VERSION 5.7 ;
  NOWIREEXTENSIONATPIN ON ;
  DIVIDERCHAR "/" ;
  BUSBITCHARS "[]" ;
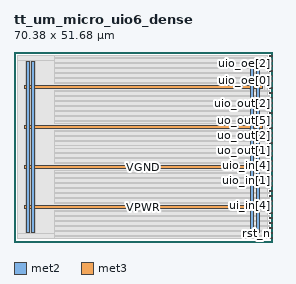
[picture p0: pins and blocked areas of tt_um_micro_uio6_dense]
MACRO tt_um_micro_uio6_dense
  CLASS BLOCK ;
  FOREIGN tt_um_micro_uio6_dense ;
  ORIGIN 0.000 0.000 ;
  SIZE 70.380 BY 51.680 ;
  PIN VGND
    DIRECTION INOUT ;
    USE GROUND ;
    PORT
      LAYER met2 ;
        RECT 4.660 2.480 5.460 49.200 ;
    END
    PORT
      LAYER met2 ;
        RECT 65.840 2.480 66.640 49.200 ;
    END
    PORT
      LAYER met3 ;
        RECT 2.760 19.900 67.620 20.900 ;
    END
    PORT
      LAYER met3 ;
        RECT 2.760 41.660 67.620 42.660 ;
    END
  END VGND
  PIN VPWR
    DIRECTION INOUT ;
    USE POWER ;
    PORT
      LAYER met2 ;
        RECT 3.280 2.480 4.080 49.200 ;
    END
    PORT
      LAYER met2 ;
        RECT 64.460 2.480 65.260 49.200 ;
    END
    PORT
      LAYER met3 ;
        RECT 2.760 9.020 67.620 10.020 ;
    END
    PORT
      LAYER met3 ;
        RECT 2.760 30.780 67.620 31.780 ;
    END
  END VPWR
  PIN clk
    DIRECTION INPUT ;
    USE SIGNAL ;
    ANTENNAGATEAREA 0.852000 ;
    PORT
      LAYER met3 ;
        RECT 69.380 0.870 70.380 1.170 ;
    END
  END clk
  PIN rst_n
    DIRECTION INPUT ;
    USE SIGNAL ;
    ANTENNAGATEAREA 0.213000 ;
    PORT
      LAYER met3 ;
        RECT 69.380 2.230 70.380 2.530 ;
    END
  END rst_n
  PIN ui_in[0]
    DIRECTION INPUT ;
    USE SIGNAL ;
    ANTENNAGATEAREA 0.213000 ;
    PORT
      LAYER met3 ;
        RECT 69.380 3.590 70.380 3.890 ;
    END
  END ui_in[0]
  PIN ui_in[1]
    DIRECTION INPUT ;
    USE SIGNAL ;
    ANTENNAGATEAREA 0.196500 ;
    PORT
      LAYER met3 ;
        RECT 69.380 4.950 70.380 5.250 ;
    END
  END ui_in[1]
  PIN ui_in[2]
    DIRECTION INPUT ;
    USE SIGNAL ;
    ANTENNAGATEAREA 0.196500 ;
    PORT
      LAYER met3 ;
        RECT 69.380 6.310 70.380 6.610 ;
    END
  END ui_in[2]
  PIN ui_in[3]
    DIRECTION INPUT ;
    USE SIGNAL ;
    ANTENNAGATEAREA 0.196500 ;
    PORT
      LAYER met3 ;
        RECT 69.380 7.670 70.380 7.970 ;
    END
  END ui_in[3]
  PIN ui_in[4]
    DIRECTION INPUT ;
    USE SIGNAL ;
    ANTENNAGATEAREA 0.213000 ;
    PORT
      LAYER met3 ;
        RECT 69.380 9.710 70.380 10.010 ;
    END
  END ui_in[4]
  PIN ui_in[5]
    DIRECTION INPUT ;
    USE SIGNAL ;
    ANTENNAGATEAREA 0.213000 ;
    PORT
      LAYER met3 ;
        RECT 69.380 11.070 70.380 11.370 ;
    END
  END ui_in[5]
  PIN ui_in[6]
    DIRECTION INPUT ;
    USE SIGNAL ;
    ANTENNAGATEAREA 0.213000 ;
    PORT
      LAYER met3 ;
        RECT 69.380 12.430 70.380 12.730 ;
    END
  END ui_in[6]
  PIN ui_in[7]
    DIRECTION INPUT ;
    USE SIGNAL ;
    ANTENNAGATEAREA 0.213000 ;
    PORT
      LAYER met3 ;
        RECT 69.380 13.790 70.380 14.090 ;
    END
  END ui_in[7]
  PIN uio_in[0]
    DIRECTION INPUT ;
    USE SIGNAL ;
    ANTENNAGATEAREA 0.213000 ;
    PORT
      LAYER met3 ;
        RECT 69.380 15.150 70.380 15.450 ;
    END
  END uio_in[0]
  PIN uio_in[1]
    DIRECTION INPUT ;
    USE SIGNAL ;
    ANTENNAGATEAREA 0.213000 ;
    PORT
      LAYER met3 ;
        RECT 69.380 16.510 70.380 16.810 ;
    END
  END uio_in[1]
  PIN uio_in[2]
    DIRECTION INPUT ;
    USE SIGNAL ;
    ANTENNAGATEAREA 0.213000 ;
    PORT
      LAYER met3 ;
        RECT 69.380 17.870 70.380 18.170 ;
    END
  END uio_in[2]
  PIN uio_in[3]
    DIRECTION INPUT ;
    USE SIGNAL ;
    ANTENNAGATEAREA 0.213000 ;
    PORT
      LAYER met3 ;
        RECT 69.380 19.230 70.380 19.530 ;
    END
  END uio_in[3]
  PIN uio_in[4]
    DIRECTION INPUT ;
    USE SIGNAL ;
    ANTENNAGATEAREA 0.213000 ;
    PORT
      LAYER met3 ;
        RECT 69.380 20.590 70.380 20.890 ;
    END
  END uio_in[4]
  PIN uio_in[5]
    DIRECTION INPUT ;
    USE SIGNAL ;
    ANTENNAGATEAREA 0.213000 ;
    PORT
      LAYER met3 ;
        RECT 69.380 21.950 70.380 22.250 ;
    END
  END uio_in[5]
  PIN uio_oe[0]
    DIRECTION OUTPUT ;
    USE SIGNAL ;
    ANTENNADIFFAREA 0.429000 ;
    PORT
      LAYER met3 ;
        RECT 69.380 43.710 70.380 44.010 ;
    END
  END uio_oe[0]
  PIN uio_oe[1]
    DIRECTION OUTPUT ;
    USE SIGNAL ;
    ANTENNADIFFAREA 0.429000 ;
    PORT
      LAYER met3 ;
        RECT 69.380 45.070 70.380 45.370 ;
    END
  END uio_oe[1]
  PIN uio_oe[2]
    DIRECTION OUTPUT ;
    USE SIGNAL ;
    ANTENNADIFFAREA 0.429000 ;
    PORT
      LAYER met3 ;
        RECT 69.380 46.430 70.380 46.730 ;
    END
  END uio_oe[2]
  PIN uio_oe[3]
    DIRECTION OUTPUT ;
    USE SIGNAL ;
    ANTENNADIFFAREA 0.429000 ;
    PORT
      LAYER met3 ;
        RECT 69.380 47.790 70.380 48.090 ;
    END
  END uio_oe[3]
  PIN uio_oe[4]
    DIRECTION OUTPUT ;
    USE SIGNAL ;
    ANTENNADIFFAREA 0.429000 ;
    PORT
      LAYER met3 ;
        RECT 69.380 49.150 70.380 49.450 ;
    END
  END uio_oe[4]
  PIN uio_oe[5]
    DIRECTION OUTPUT ;
    USE SIGNAL ;
    ANTENNADIFFAREA 0.429000 ;
    PORT
      LAYER met3 ;
        RECT 69.380 50.510 70.380 50.810 ;
    END
  END uio_oe[5]
  PIN uio_out[0]
    DIRECTION OUTPUT ;
    USE SIGNAL ;
    ANTENNADIFFAREA 0.429000 ;
    PORT
      LAYER met3 ;
        RECT 69.380 34.870 70.380 35.170 ;
    END
  END uio_out[0]
  PIN uio_out[1]
    DIRECTION OUTPUT ;
    USE SIGNAL ;
    ANTENNADIFFAREA 0.445500 ;
    PORT
      LAYER met3 ;
        RECT 69.380 36.230 70.380 36.530 ;
    END
  END uio_out[1]
  PIN uio_out[2]
    DIRECTION OUTPUT ;
    USE SIGNAL ;
    ANTENNADIFFAREA 0.445500 ;
    PORT
      LAYER met3 ;
        RECT 69.380 37.590 70.380 37.890 ;
    END
  END uio_out[2]
  PIN uio_out[3]
    DIRECTION OUTPUT ;
    USE SIGNAL ;
    ANTENNADIFFAREA 0.429000 ;
    PORT
      LAYER met3 ;
        RECT 69.380 38.950 70.380 39.250 ;
    END
  END uio_out[3]
  PIN uio_out[4]
    DIRECTION OUTPUT ;
    USE SIGNAL ;
    ANTENNADIFFAREA 0.445500 ;
    PORT
      LAYER met3 ;
        RECT 69.380 40.310 70.380 40.610 ;
    END
  END uio_out[4]
  PIN uio_out[5]
    DIRECTION OUTPUT ;
    USE SIGNAL ;
    ANTENNADIFFAREA 0.445500 ;
    PORT
      LAYER met3 ;
        RECT 69.380 41.670 70.380 41.970 ;
    END
  END uio_out[5]
  PIN uo_out[0]
    DIRECTION OUTPUT ;
    USE SIGNAL ;
    ANTENNADIFFAREA 0.429000 ;
    PORT
      LAYER met3 ;
        RECT 69.380 23.310 70.380 23.610 ;
    END
  END uo_out[0]
  PIN uo_out[1]
    DIRECTION OUTPUT ;
    USE SIGNAL ;
    ANTENNADIFFAREA 0.429000 ;
    PORT
      LAYER met3 ;
        RECT 69.380 24.670 70.380 24.970 ;
    END
  END uo_out[1]
  PIN uo_out[2]
    DIRECTION OUTPUT ;
    USE SIGNAL ;
    ANTENNADIFFAREA 0.429000 ;
    PORT
      LAYER met3 ;
        RECT 69.380 26.710 70.380 27.010 ;
    END
  END uo_out[2]
  PIN uo_out[3]
    DIRECTION OUTPUT ;
    USE SIGNAL ;
    ANTENNADIFFAREA 0.429000 ;
    PORT
      LAYER met3 ;
        RECT 69.380 28.070 70.380 28.370 ;
    END
  END uo_out[3]
  PIN uo_out[4]
    DIRECTION OUTPUT ;
    USE SIGNAL ;
    ANTENNADIFFAREA 0.462000 ;
    PORT
      LAYER met3 ;
        RECT 69.380 29.430 70.380 29.730 ;
    END
  END uo_out[4]
  PIN uo_out[5]
    DIRECTION OUTPUT ;
    USE SIGNAL ;
    ANTENNADIFFAREA 0.445500 ;
    PORT
      LAYER met3 ;
        RECT 69.380 30.790 70.380 31.090 ;
    END
  END uo_out[5]
  PIN uo_out[6]
    DIRECTION OUTPUT ;
    USE SIGNAL ;
    ANTENNADIFFAREA 0.445500 ;
    PORT
      LAYER met3 ;
        RECT 69.380 32.150 70.380 32.450 ;
    END
  END uo_out[6]
  PIN uo_out[7]
    DIRECTION OUTPUT ;
    USE SIGNAL ;
    ANTENNADIFFAREA 0.445500 ;
    PORT
      LAYER met3 ;
        RECT 69.380 33.510 70.380 33.810 ;
    END
  END uo_out[7]
  OBS
      LAYER nwell ;
        RECT 2.570 2.635 67.810 49.150 ;
      LAYER li1 ;
        RECT 2.760 2.635 67.620 49.045 ;
      LAYER met1 ;
        RECT 0.990 1.400 68.470 49.200 ;
      LAYER met2 ;
        RECT 1.020 49.480 68.450 50.845 ;
        RECT 1.020 2.200 3.000 49.480 ;
        RECT 4.360 2.200 4.380 49.480 ;
        RECT 5.740 2.200 64.180 49.480 ;
        RECT 65.540 2.200 65.560 49.480 ;
        RECT 66.920 2.200 68.450 49.480 ;
        RECT 1.020 0.835 68.450 2.200 ;
      LAYER met3 ;
        RECT 11.105 50.110 68.980 50.825 ;
        RECT 11.105 49.850 69.380 50.110 ;
        RECT 11.105 48.750 68.980 49.850 ;
        RECT 11.105 48.490 69.380 48.750 ;
        RECT 11.105 47.390 68.980 48.490 ;
        RECT 11.105 47.130 69.380 47.390 ;
        RECT 11.105 46.030 68.980 47.130 ;
        RECT 11.105 45.770 69.380 46.030 ;
        RECT 11.105 44.670 68.980 45.770 ;
        RECT 11.105 44.410 69.380 44.670 ;
        RECT 11.105 43.310 68.980 44.410 ;
        RECT 11.105 43.060 69.380 43.310 ;
        RECT 68.020 42.370 69.380 43.060 ;
        RECT 68.020 41.270 68.980 42.370 ;
        RECT 68.020 41.260 69.380 41.270 ;
        RECT 11.105 41.010 69.380 41.260 ;
        RECT 11.105 39.910 68.980 41.010 ;
        RECT 11.105 39.650 69.380 39.910 ;
        RECT 11.105 38.550 68.980 39.650 ;
        RECT 11.105 38.290 69.380 38.550 ;
        RECT 11.105 37.190 68.980 38.290 ;
        RECT 11.105 36.930 69.380 37.190 ;
        RECT 11.105 35.830 68.980 36.930 ;
        RECT 11.105 35.570 69.380 35.830 ;
        RECT 11.105 34.470 68.980 35.570 ;
        RECT 11.105 34.210 69.380 34.470 ;
        RECT 11.105 33.110 68.980 34.210 ;
        RECT 11.105 32.850 69.380 33.110 ;
        RECT 11.105 32.180 68.980 32.850 ;
        RECT 68.020 31.750 68.980 32.180 ;
        RECT 68.020 31.490 69.380 31.750 ;
        RECT 68.020 30.390 68.980 31.490 ;
        RECT 68.020 30.380 69.380 30.390 ;
        RECT 11.105 30.130 69.380 30.380 ;
        RECT 11.105 29.030 68.980 30.130 ;
        RECT 11.105 28.770 69.380 29.030 ;
        RECT 11.105 27.670 68.980 28.770 ;
        RECT 11.105 27.410 69.380 27.670 ;
        RECT 11.105 26.310 68.980 27.410 ;
        RECT 11.105 25.370 69.380 26.310 ;
        RECT 11.105 24.270 68.980 25.370 ;
        RECT 11.105 24.010 69.380 24.270 ;
        RECT 11.105 22.910 68.980 24.010 ;
        RECT 11.105 22.650 69.380 22.910 ;
        RECT 11.105 21.550 68.980 22.650 ;
        RECT 11.105 21.300 69.380 21.550 ;
        RECT 68.020 21.290 69.380 21.300 ;
        RECT 68.020 20.190 68.980 21.290 ;
        RECT 68.020 19.930 69.380 20.190 ;
        RECT 68.020 19.500 68.980 19.930 ;
        RECT 11.105 18.830 68.980 19.500 ;
        RECT 11.105 18.570 69.380 18.830 ;
        RECT 11.105 17.470 68.980 18.570 ;
        RECT 11.105 17.210 69.380 17.470 ;
        RECT 11.105 16.110 68.980 17.210 ;
        RECT 11.105 15.850 69.380 16.110 ;
        RECT 11.105 14.750 68.980 15.850 ;
        RECT 11.105 14.490 69.380 14.750 ;
        RECT 11.105 13.390 68.980 14.490 ;
        RECT 11.105 13.130 69.380 13.390 ;
        RECT 11.105 12.030 68.980 13.130 ;
        RECT 11.105 11.770 69.380 12.030 ;
        RECT 11.105 10.670 68.980 11.770 ;
        RECT 11.105 10.420 69.380 10.670 ;
        RECT 68.020 10.410 69.380 10.420 ;
        RECT 68.020 9.310 68.980 10.410 ;
        RECT 68.020 8.620 69.380 9.310 ;
        RECT 11.105 8.370 69.380 8.620 ;
        RECT 11.105 7.270 68.980 8.370 ;
        RECT 11.105 7.010 69.380 7.270 ;
        RECT 11.105 5.910 68.980 7.010 ;
        RECT 11.105 5.650 69.380 5.910 ;
        RECT 11.105 4.550 68.980 5.650 ;
        RECT 11.105 4.290 69.380 4.550 ;
        RECT 11.105 3.190 68.980 4.290 ;
        RECT 11.105 2.930 69.380 3.190 ;
        RECT 11.105 1.830 68.980 2.930 ;
        RECT 11.105 1.570 69.380 1.830 ;
        RECT 11.105 0.855 68.980 1.570 ;
  END
END tt_um_micro_uio6_dense
END LIBRARY

